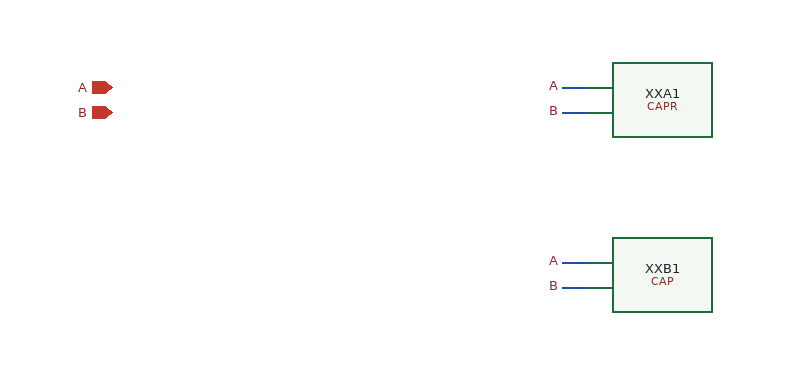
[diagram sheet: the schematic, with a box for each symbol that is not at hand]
v {xschem version=3.0.0 file_version=1.2 }
G {}
K {}
V {}
S {}
E {}
C {devices/iopin.sym} 0 0 0 0 {name=p0 lab=A}
C {devices/iopin.sym} 0 20 0 0 {name=p1 lab=B}
C {SAR9B/CAPR.sym} 400 0 0 0 {name=XXA1}
N 360.0 0.0 380.0 0.0 {lab=A}
C {devices/lab_pin.sym} 360.0 0.0 0 0 {name=l0 sig_type=std_logic lab=A }
N 360.0 20.0 380.0 20.0 {lab=B}
C {devices/lab_pin.sym} 360.0 20.0 0 0 {name=l1 sig_type=std_logic lab=B }
C {SAR9B/CAP.sym} 400 140.0 0 0 {name=XXB1}
N 360.0 140.0 380.0 140.0 {lab=A}
C {devices/lab_pin.sym} 360.0 140.0 0 0 {name=l2 sig_type=std_logic lab=A }
N 360.0 160.0 380.0 160.0 {lab=B}
C {devices/lab_pin.sym} 360.0 160.0 0 0 {name=l3 sig_type=std_logic lab=B }
